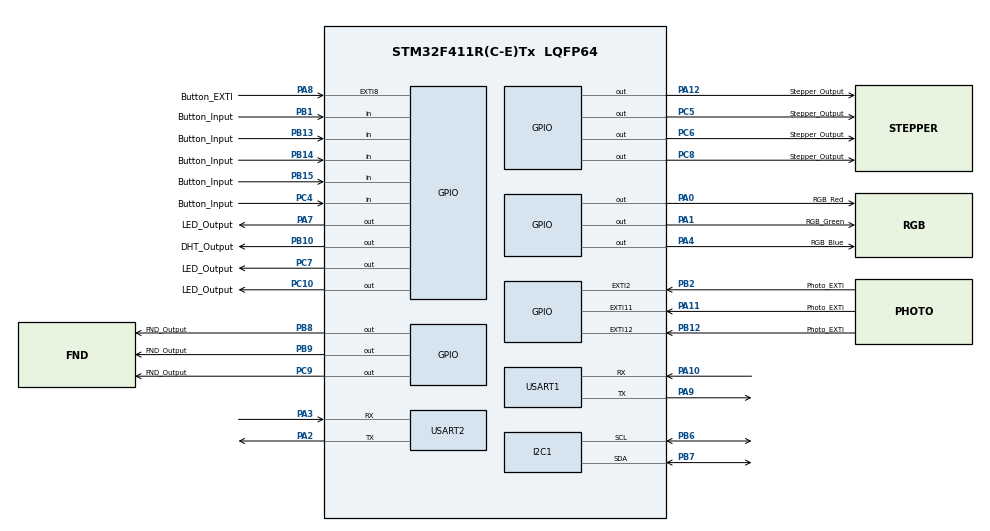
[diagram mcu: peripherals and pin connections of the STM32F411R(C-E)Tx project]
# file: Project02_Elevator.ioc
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IWDG.Prescaler=IWDG_PRESCALER_64
IWDG.Reload=2000
Mcu.Family=STM32F4
Mcu.Name=STM32F411R(C-E)Tx
Mcu.Package=LQFP64
NVIC.EXTI15_10_IRQn=true\:1\:0\:true\:false\:true\:true\:true\:true
NVIC.EXTI2_IRQn=true\:1\:0\:true\:false\:true\:true\:true\:true
NVIC.EXTI9_5_IRQn=true\:0\:0\:false\:false\:true\:true\:true\:true
NVIC.PriorityGroup=NVIC_PRIORITYGROUP_4
NVIC.USART1_IRQn=true\:0\:0\:false\:false\:true\:true\:true\:true
PA0-WKUP.GPIO_Label=RGB_Red
PA0-WKUP.Signal=GPIO_Output
PA1.GPIO_Label=RGB_Green
PA1.Signal=GPIO_Output
PA10.Mode=Asynchronous
PA10.Signal=USART1_RX
PA11.GPIO_Label=Photo_EXTI
PA11.GPIO_ModeDefaultEXTI=GPIO_MODE_IT_FALLING
PA11.GPIO_PuPd=GPIO_PULLUP
PA11.Signal=GPXTI11
PA12.GPIO_Label=Stepper_Output
PA12.Signal=GPIO_Output
PA13.Mode=Serial_Wire
PA13.Signal=SYS_JTMS-SWDIO
PA14.Mode=Serial_Wire
PA14.Signal=SYS_JTCK-SWCLK
PA2.Mode=Asynchronous
PA2.Signal=USART2_TX
PA3.Mode=Asynchronous
PA3.Signal=USART2_RX
PA4.GPIO_Label=RGB_Blue
PA4.Signal=GPIO_Output
PA5.GPIO_Label=Buzzer_TIM2
PA5.Signal=S_TIM2_CH1_ETR
PA6.GPIO_Label=Servo_TIM3
PA6.Signal=S_TIM3_CH1
PA7.GPIO_Label=LED_Output
PA7.Signal=GPIO_Output
PA8.GPIO_Label=Button_EXTI
PA8.GPIO_ModeDefaultEXTI=GPIO_MODE_IT_FALLING
PA8.GPIO_PuPd=GPIO_PULLUP
PA8.Signal=GPXTI8
PA9.Mode=Asynchronous
PA9.Signal=USART1_TX
PB1.GPIO_Label=Button_Input
PB1.GPIO_PuPd=GPIO_PULLUP
PB1.Signal=GPIO_Input
PB10.GPIO_Label=DHT_Output
PB10.GPIO_Speed=GPIO_SPEED_FREQ_HIGH
PB10.PinState=GPIO_PIN_SET
PB10.Signal=GPIO_Output
PB12.GPIO_Label=Photo_EXTI
PB12.GPIO_ModeDefaultEXTI=GPIO_MODE_IT_FALLING
PB12.GPIO_PuPd=GPIO_PULLUP
PB12.Signal=GPXTI12
PB13.GPIO_Label=Button_Input
PB13.GPIO_PuPd=GPIO_PULLUP
PB13.Signal=GPIO_Input
PB14.GPIO_Label=Button_Input
PB14.GPIO_PuPd=GPIO_PULLUP
PB14.Signal=GPIO_Input
PB15.GPIO_Label=Button_Input
PB15.GPIO_PuPd=GPIO_PULLUP
PB15.Signal=GPIO_Input
PB2.GPIO_Label=Photo_EXTI
PB2.GPIO_ModeDefaultEXTI=GPIO_MODE_IT_FALLING
PB2.GPIO_PuPd=GPIO_PULLUP
PB2.Signal=GPXTI2
PB6.Mode=I2C
PB6.Signal=I2C1_SCL
PB7.Mode=I2C
PB7.Signal=I2C1_SDA
PB8.GPIO_Label=FND_Output
PB8.Signal=GPIO_Output
PB9.GPIO_Label=FND_Output
PB9.Signal=GPIO_Output
PC10.GPIO_Label=LED_Output
PC10.Signal=GPIO_Output
PC4.GPIO_Label=Button_Input
PC4.GPIO_PuPd=GPIO_PULLUP
PC4.Signal=GPIO_Input
PC5.GPIO_Label=Stepper_Output
PC5.Signal=GPIO_Output
PC6.GPIO_Label=Stepper_Output
PC6.Signal=GPIO_Output
PC7.GPIO_Label=LED_Output
PC7.Signal=GPIO_Output
PC8.GPIO_Label=Stepper_Output
PC8.Signal=GPIO_Output
PC9.GPIO_Label=FND_Output
PC9.Signal=GPIO_Output
PH0\ -\ OSC_IN.Mode=HSE-External-Clock-Source
PH0\ -\ OSC_IN.Signal=RCC_OSC_IN
PH1\ -\ OSC_OUT.Mode=HSE-External-Clock-Source
PH1\ -\ OSC_OUT.Signal=RCC_OSC_OUT
ProjectManager.HeapSize=0x200
ProjectManager.StackSize=0x400
ProjectManager.TargetToolchain=STM32CubeIDE
RCC.48MHZClocksFreq_Value=50000000
RCC.AHBFreq_Value=100000000
RCC.APB1CLKDivider=RCC_HCLK_DIV2
RCC.APB1Freq_Value=50000000
RCC.APB1TimFreq_Value=100000000
RCC.APB2Freq_Value=100000000
RCC.APB2TimFreq_Value=100000000
RCC.CortexFreq_Value=100000000
RCC.HCLKFreq_Value=100000000
RCC.HSE_VALUE=8000000
RCC.HSI_VALUE=16000000

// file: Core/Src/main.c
/* USER CODE BEGIN Header */
/**
  ******************************************************************************
  * @file           : main.c
  * @brief          : Main program body — Elevator Control
  ******************************************************************************
  */
/* USER CODE END Header */
#include "main.h"
#include "i2c.h"
#include "iwdg.h"
#include "tim.h"
#include "usart.h"
#include "gpio.h"

/* USER CODE BEGIN Includes */
#include <stdio.h>
#include "app_elevator_fsm.h"
#include "dev_display.h"
#include "dev_photo.h"
#include "dev_stepper.h"
#include "dev_servo.h"
#include "dev_buzzer.h"
#include "dev_dht.h"
#include "app_rs485_ctrl.h"

/* USER CODE END Includes */

/* USER CODE BEGIN PV */
/* 아래 전역들은 ISR과 메인루프가 함께 읽고 쓰므로 전부 volatile.
   App/BSP 레이어에서 extern으로 참조한다. */
volatile uint8_t  current_floor   = 1;   // 현재 층 — 포토센서 ISR이 갱신
volatile uint8_t  target_floor    = 1;   // 목표 층 — 층 버튼 및 RS-485 원격 명령이 설정
volatile uint8_t  emergency_active = 0;  // 비상정지(E401) 플래그 — PA8 EXTI ISR이 세팅
volatile uint8_t  inspection_active = 0; // 점검모드(E402) 플래그 — 관제실 RS-485 명령으로 세팅/해제
volatile uint8_t  move_timeout_active = 0;   // 이동 타임아웃(E201) 플래그 — FSM이 세팅, 관제실 리셋으로 해제
volatile uint8_t  floor_skip_active   = 0;   // 층 건너뜀(E301) 플래그 — FSM이 세팅, 관제실 리셋으로 해제
volatile uint8_t  floor2_transit_flag = 0;   // 이번 이동 중 2층 센서를 지나쳤는지 — 1<->3층 이동의 E301 판정용
/* USER CODE END PV */

void SystemClock_Config(void);

int main(void)
{

  /* MCU Configuration--------------------------------------------------------*/

  /* Reset of all peripherals, Initializes the Flash interface and the Systick. */
  HAL_Init();

  /* Configure the system clock */
  SystemClock_Config();

  /* Initialize all configured peripherals */
  MX_GPIO_Init();
  MX_TIM3_Init();
  MX_USART1_UART_Init();
  MX_USART2_UART_Init();
  MX_IWDG_Init();
  MX_TIM2_Init();
  MX_TIM5_Init();
  MX_I2C1_Init();
  /* USER CODE BEGIN 2 */
  HAL_TIM_Base_Start(&htim5);
  DHT_Init();
  Modbus_Init();
  Servo_Init();
  FND_Shift_Data(current_floor);
  Elevator_FSM_Init();               // FSM 초기화 + Display_Init(RGB+LCD) + 부팅 시 실제 층 감지(호밍)
  printf("=== Elevator Start ===\r\n");

  uint32_t last_alive_tick = 0;
  /* USER CODE END 2 */

  /* Infinite loop */
  while (1)
  {

    /* USER CODE BEGIN 3 */

    /* 비상·점검 감지, 버튼 처리, 5-state(IDLE/MOVING/DOOR_OPEN/ERROR/INSPECTION) 전이,
       모터 스텝, 상태표시(RGB+LCD)를 한 번에 처리 */
    Elevator_FSM_Update();

    /* ERROR/INSPECTION 상태에서도 매 tick 계속 돌아야 하는 논블로킹 서비스들.
       (비상 중에도 부저 엔벨로프·LED 점멸·FND 스캔·DHT 측정·Modbus 응답이 멈추면 안 됨) */
    LED_Bar_Update();
    Buzzer_Update();
    FND_Scan();
    DHT_Update();
    Modbus_Update();

    /* 1초 주기 생존 로그 — 현재층·목표층·FSM 상태를 UART로 확인 */
    if (HAL_GetTick() - last_alive_tick >= 1000)
    {
        printf("Alive floor=%d target=%d state=%d\r\n",
               current_floor, target_floor, (int)Elevator_FSM_GetState());
        last_alive_tick = HAL_GetTick();
    }

    /* IWDG 리프레시 — 루프 맨 끝에 두어 위쪽 서비스가 전부 끝난 뒤에만 도달하게 한다.
       중간에서 리프레시하면 블로킹 I2C(LCD) 등이 멎어도 워치독이 리셋을 못 건다. */
    HAL_IWDG_Refresh(&hiwdg);

  }
  /* USER CODE END 3 */
}

void SystemClock_Config(void)
{
  RCC_OscInitTypeDef RCC_OscInitStruct = {0};
  RCC_ClkInitTypeDef RCC_ClkInitStruct = {0};

  /** Configure the main internal regulator output voltage
  */
  __HAL_RCC_PWR_CLK_ENABLE();
  __HAL_PWR_VOLTAGESCALING_CONFIG(PWR_REGULATOR_VOLTAGE_SCALE1);

  /** Initializes the RCC Oscillators according to the specified parameters
  * in the RCC_OscInitTypeDef structure.
  */
  RCC_OscInitStruct.OscillatorType = RCC_OSCILLATORTYPE_LSI|RCC_OSCILLATORTYPE_HSE;
  RCC_OscInitStruct.HSEState = RCC_HSE_BYPASS;
  RCC_OscInitStruct.LSIState = RCC_LSI_ON;
  RCC_OscInitStruct.PLL.PLLState = RCC_PLL_ON;
  RCC_OscInitStruct.PLL.PLLSource = RCC_PLLSOURCE_HSE;
  RCC_OscInitStruct.PLL.PLLM = 4;
  RCC_OscInitStruct.PLL.PLLN = 100;
  RCC_OscInitStruct.PLL.PLLP = RCC_PLLP_DIV2;
  RCC_OscInitStruct.PLL.PLLQ = 4;
  if (HAL_RCC_OscConfig(&RCC_OscInitStruct) != HAL_OK)
  {
    Error_Handler();
  }

  /** Initializes the CPU, AHB and APB buses clocks
  */
  RCC_ClkInitStruct.ClockType = RCC_CLOCKTYPE_HCLK|RCC_CLOCKTYPE_SYSCLK
                              |RCC_CLOCKTYPE_PCLK1|RCC_CLOCKTYPE_PCLK2;
  RCC_ClkInitStruct.SYSCLKSource = RCC_SYSCLKSOURCE_PLLCLK;
  RCC_ClkInitStruct.AHBCLKDivider = RCC_SYSCLK_DIV1;
  RCC_ClkInitStruct.APB1CLKDivider = RCC_HCLK_DIV2;
  RCC_ClkInitStruct.APB2CLKDivider = RCC_HCLK_DIV1;

  if (HAL_RCC_ClockConfig(&RCC_ClkInitStruct, FLASH_LATENCY_3) != HAL_OK)
  {
    Error_Handler();
  }
}

/* USER CODE BEGIN 4 */

/* printf 리타겟 → USART2 디버그 출력. USART1은 RS-485 통신 전용이라 쓰지 않는다. */
int __io_putchar(int ch)
{
    if (ch == '\n')
        HAL_UART_Transmit(&huart2, (uint8_t *)"\r", 1, 0xFFFF);
    HAL_UART_Transmit(&huart2, (uint8_t *)&ch, 1, 0xFFFF);
    return ch;
}

/* EXTI 공통 콜백 — 비상정지 버튼(PA8)과 층 포토센서(PA11/PB12/PB2)가 함께 들어온다. */
void HAL_GPIO_EXTI_Callback(uint16_t GPIO_Pin)
{
    if (GPIO_Pin == GPIO_PIN_8)   // PA8 = 비상정지 버튼. EXTI9_5 우선순위 0으로 포토센서(1)보다 앞선다
    {
        if (!emergency_active)    // 이미 비상 상태면 중복 처리 불필요
        {
            emergency_active = 1;
            Motor_Stop();         // 모터 즉시 정지 — 메인루프를 기다리지 않고 ISR에서 바로 끊는다
        }
        return;
    }

    /* 포토센서: current_floor 갱신 + 목표층 도달 시 Motor_Stop()만 수행.
       LED·부저·문 등 도착 후처리는 ISR에서 하지 않는다. 부저 엔벨로프처럼
       주기적 갱신이 필요한 동작은 메인루프의 Elevator_FSM_Update()에서 일괄 처리. */
    Handle_Photo_Interrupt(GPIO_Pin);
}

/* USER CODE END 4 */

void Error_Handler(void)
{
  __disable_irq();
  while (1) {}
}
